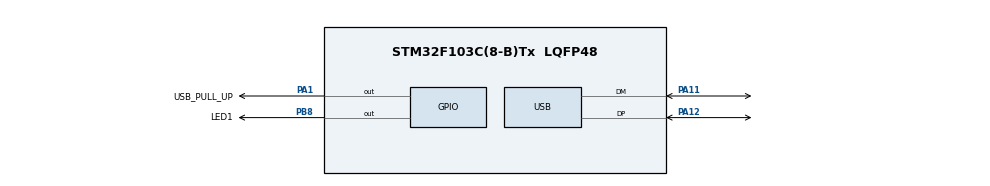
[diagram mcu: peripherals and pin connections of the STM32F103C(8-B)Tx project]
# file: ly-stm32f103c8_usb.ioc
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Mcu.Family=STM32F1
Mcu.Name=STM32F103C(8-B)Tx
Mcu.Package=LQFP48
NVIC.PriorityGroup=NVIC_PRIORITYGROUP_4
NVIC.USB_LP_CAN1_RX0_IRQn=true\:0\:0\:false\:false\:true\:false\:true
PA1.GPIO_Label=USB_PULL_UP
PA1.Signal=GPIO_Output
PA11.Mode=Device
PA11.Signal=USB_DM
PA12.Mode=Device
PA12.Signal=USB_DP
PA13.Mode=Serial_Wire
PA13.Signal=SYS_JTMS-SWDIO
PA14.Mode=Serial_Wire
PA14.Signal=SYS_JTCK-SWCLK
PB8.GPIO_Label=LED1
PB8.Signal=GPIO_Output
PC14-OSC32_IN.Mode=LSE-External-Oscillator
PC14-OSC32_IN.Signal=RCC_OSC32_IN
PC15-OSC32_OUT.Mode=LSE-External-Oscillator
PC15-OSC32_OUT.Signal=RCC_OSC32_OUT
PD0-OSC_IN.Mode=HSE-External-Oscillator
PD0-OSC_IN.Signal=RCC_OSC_IN
PD1-OSC_OUT.Mode=HSE-External-Oscillator
PD1-OSC_OUT.Signal=RCC_OSC_OUT
ProjectManager.HeapSize=0x200
ProjectManager.StackSize=0x400
ProjectManager.TargetToolchain=EWARM V8.32
RCC.AHBFreq_Value=72000000
RCC.APB1CLKDivider=RCC_HCLK_DIV2
RCC.APB1Freq_Value=36000000
RCC.APB1TimFreq_Value=72000000
RCC.APB2Freq_Value=72000000
RCC.APB2TimFreq_Value=72000000
RCC.HCLKFreq_Value=72000000
RCC.PLLMUL=RCC_PLL_MUL9
RCC.SYSCLKFreq_VALUE=72000000
RCC.SYSCLKSource=RCC_SYSCLKSOURCE_PLLCLK
RCC.USBFreq_Value=48000000
RCC.USBPrescaler=RCC_USBCLKSOURCE_PLL_DIV1_5
USB_DEVICE.CLASS_NAME_FS=CDC
USB_DEVICE.VirtualMode=Cdc
USB_DEVICE.VirtualModeFS=Cdc_FS
VP_USB_DEVICE_VS_USB_DEVICE_CDC_FS.Mode=CDC_FS
board=custom

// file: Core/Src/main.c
/* USER CODE BEGIN Header */
/**
  ******************************************************************************
  * @file           : main.c
  * @brief          : Main program body
  ******************************************************************************
  * @attention
  *
  * <h2><center>&copy; Copyright (c) 2021 STMicroelectronics.
  * All rights reserved.</center></h2>
  *
  * This software component is licensed by ST under Ultimate Liberty license
  * SLA0044, the "License"; You may not use this file except in compliance with
  * the License. You may obtain a copy of the License at:
  *                             www.st.com/SLA0044
  *   https://jeonhj.tistory.com/29
  ******************************************************************************
  */
/* USER CODE END Header */
#include "main.h"
#include "usb_device.h"

/* USER CODE BEGIN PV */
#define APP_RX_DATA_SIZE 64
#define APP_TX_DATA_SIZE 64
extern uint8_t UserRxBufferFS[APP_RX_DATA_SIZE];
extern uint8_t UserTxBufferFS[APP_TX_DATA_SIZE];
/* USER CODE END PV */

void SystemClock_Config(void);
static void MX_GPIO_Init(void);

/* USER CODE BEGIN 0 */
int _write(int file, char *ptr, int len){
    //HAL_UART_Transmit(&huart1, (uint8_t*)ptr, len, 100);
    // USB로 ptr를 출력합니다.
    CDC_Transmit_FS(ptr, len);
    return (len);
}
/* USER CODE END 0 */

int main(void)
{
  /* USER CODE BEGIN 1 */
  static uint32_t time = 0;
  char array[] = {"Hello_CDC_TEST!!!\n\r"};
  char *prt1 = array;

  /* USER CODE END 1 */

  /* MCU Configuration--------------------------------------------------------*/

  /* Reset of all peripherals, Initializes the Flash interface and the Systick. */
  HAL_Init();

  /* Configure the system clock */
  SystemClock_Config();

  /* Initialize all configured peripherals */
  MX_GPIO_Init();
  MX_USB_DEVICE_Init();
  /* USER CODE BEGIN 2 */
  HAL_GPIO_WritePin(USB_PULL_UP_GPIO_Port, USB_PULL_UP_Pin, GPIO_PIN_SET);
  /* USER CODE END 2 */

  /* Infinite loop */
  while (1)
  {
     uint16_t len = strlen((const char*)UserRxBufferFS);

    if(len > 0)
    {
      strncpy((char *)UserTxBufferFS, (const char*)UserRxBufferFS, len);
      strcat((char *)UserTxBufferFS, "\r\n");
      CDC_Transmit_FS((uint8_t*)UserTxBufferFS, strlen((const char*)UserTxBufferFS));
      memset(UserRxBufferFS, 0, sizeof(UserRxBufferFS));
      memset(UserTxBufferFS, 0, sizeof(UserTxBufferFS));
    }

    HAL_Delay(500);

//    if (HAL_GetTick() - time > 1000) {
//      time = HAL_GetTick();
////      printf("Hello CDC Test\r\n");
//      CDC_Transmit_FS(prt1, sizeof(array));
//      HAL_GPIO_TogglePin(LED1_GPIO_Port, LED1_Pin);
//    }
////    HAL_Delay(200);
////    HAL_GPIO_TogglePin(LED1_GPIO_Port, LED1_Pin);
//
//    /* USER CODE BEGIN 3 */
  }
  /* USER CODE END 3 */
}

void SystemClock_Config(void)
{
  RCC_OscInitTypeDef RCC_OscInitStruct = {0};
  RCC_ClkInitTypeDef RCC_ClkInitStruct = {0};
  RCC_PeriphCLKInitTypeDef PeriphClkInit = {0};

  /** Initializes the RCC Oscillators according to the specified parameters
  * in the RCC_OscInitTypeDef structure.
  */
  RCC_OscInitStruct.OscillatorType = RCC_OSCILLATORTYPE_HSE;
  RCC_OscInitStruct.HSEState = RCC_HSE_ON;
  RCC_OscInitStruct.HSEPredivValue = RCC_HSE_PREDIV_DIV1;
  RCC_OscInitStruct.HSIState = RCC_HSI_ON;
  RCC_OscInitStruct.PLL.PLLState = RCC_PLL_ON;
  RCC_OscInitStruct.PLL.PLLSource = RCC_PLLSOURCE_HSE;
  RCC_OscInitStruct.PLL.PLLMUL = RCC_PLL_MUL6;
  if (HAL_RCC_OscConfig(&RCC_OscInitStruct) != HAL_OK)
  {
    Error_Handler();
  }
  /** Initializes the CPU, AHB and APB buses clocks
  */
  RCC_ClkInitStruct.ClockType = RCC_CLOCKTYPE_HCLK|RCC_CLOCKTYPE_SYSCLK
                              |RCC_CLOCKTYPE_PCLK1|RCC_CLOCKTYPE_PCLK2;
  RCC_ClkInitStruct.SYSCLKSource = RCC_SYSCLKSOURCE_PLLCLK;
  RCC_ClkInitStruct.AHBCLKDivider = RCC_SYSCLK_DIV1;
  RCC_ClkInitStruct.APB1CLKDivider = RCC_HCLK_DIV2;
  RCC_ClkInitStruct.APB2CLKDivider = RCC_HCLK_DIV1;

  if (HAL_RCC_ClockConfig(&RCC_ClkInitStruct, FLASH_LATENCY_1) != HAL_OK)
  {
    Error_Handler();
  }
  PeriphClkInit.PeriphClockSelection = RCC_PERIPHCLK_USB;
  PeriphClkInit.UsbClockSelection = RCC_USBCLKSOURCE_PLL;
  if (HAL_RCCEx_PeriphCLKConfig(&PeriphClkInit) != HAL_OK)
  {
    Error_Handler();
  }
}

static void MX_GPIO_Init(void)
{
  GPIO_InitTypeDef GPIO_InitStruct = {0};

  /* GPIO Ports Clock Enable */
  __HAL_RCC_GPIOC_CLK_ENABLE();
  __HAL_RCC_GPIOD_CLK_ENABLE();
  __HAL_RCC_GPIOA_CLK_ENABLE();
  __HAL_RCC_GPIOB_CLK_ENABLE();

  /*Configure GPIO pin Output Level */
  HAL_GPIO_WritePin(USB_PULL_UP_GPIO_Port, USB_PULL_UP_Pin, GPIO_PIN_RESET);

  /*Configure GPIO pin Output Level */
  HAL_GPIO_WritePin(LED1_GPIO_Port, LED1_Pin, GPIO_PIN_RESET);

  /*Configure GPIO pin : USB_PULL_UP_Pin */
  GPIO_InitStruct.Pin = USB_PULL_UP_Pin;
  GPIO_InitStruct.Mode = GPIO_MODE_OUTPUT_PP;
  GPIO_InitStruct.Pull = GPIO_NOPULL;
  GPIO_InitStruct.Speed = GPIO_SPEED_FREQ_LOW;
  HAL_GPIO_Init(USB_PULL_UP_GPIO_Port, &GPIO_InitStruct);

  /*Configure GPIO pin : LED1_Pin */
  GPIO_InitStruct.Pin = LED1_Pin;
  GPIO_InitStruct.Mode = GPIO_MODE_OUTPUT_PP;
  GPIO_InitStruct.Pull = GPIO_NOPULL;
  GPIO_InitStruct.Speed = GPIO_SPEED_FREQ_LOW;
  HAL_GPIO_Init(LED1_GPIO_Port, &GPIO_InitStruct);

}

void Error_Handler(void)
{
  __disable_irq();
  while (1)
  {
  }
}

/************************ (C) COPYRIGHT STMicroelectronics *****END OF FILE****/
